VERSION 5.7 ;
  NOWIREEXTENSIONATPIN ON ;
  DIVIDERCHAR "/" ;
  BUSBITCHARS "[]" ;
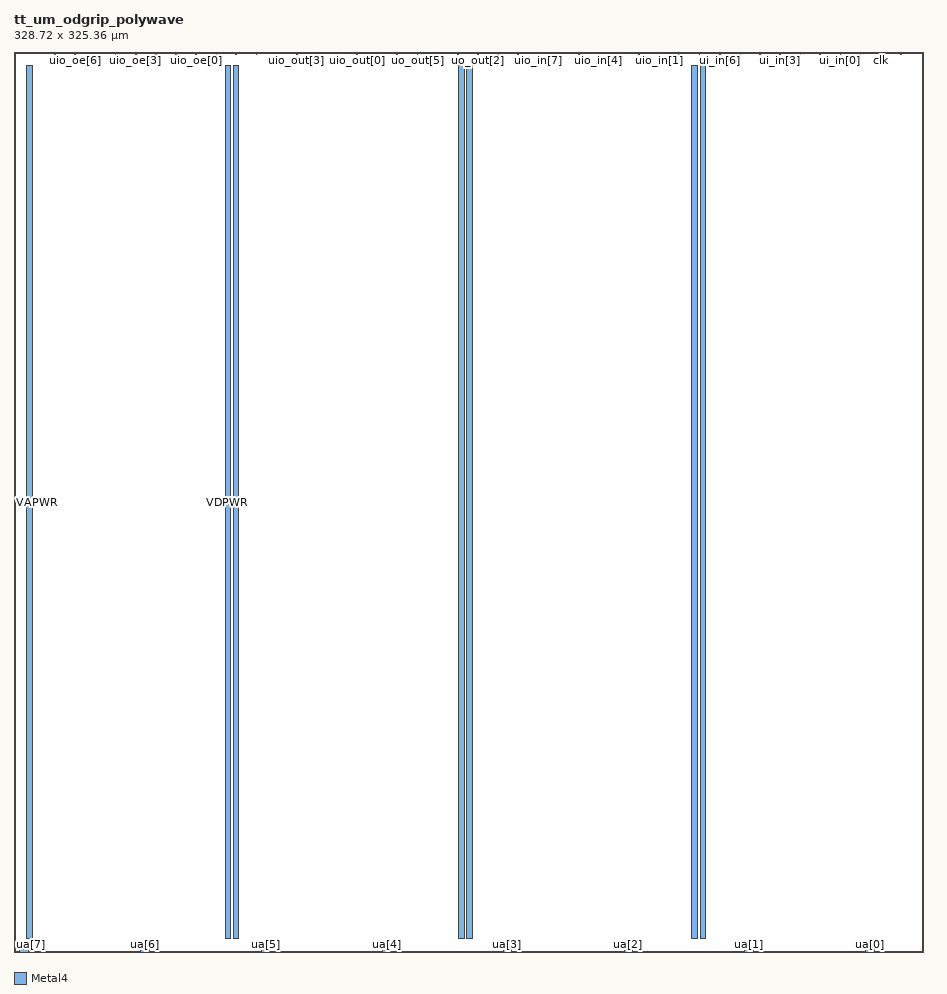
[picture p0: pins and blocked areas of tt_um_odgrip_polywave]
MACRO tt_um_odgrip_polywave
  CLASS BLOCK ;
  FOREIGN tt_um_odgrip_polywave ;
  ORIGIN 0.000 0.000 ;
  SIZE 328.720 BY 325.360 ;
  PIN clk
    DIRECTION INPUT ;
    USE SIGNAL ;
    PORT
      LAYER Metal4 ;
        RECT 313.170 324.360 313.470 325.360 ;
    END
  END clk
  PIN ena
    DIRECTION INPUT ;
    USE SIGNAL ;
    PORT
      LAYER Metal4 ;
        RECT 320.450 324.360 320.750 325.360 ;
    END
  END ena
  PIN rst_n
    DIRECTION INPUT ;
    USE SIGNAL ;
    PORT
      LAYER Metal4 ;
        RECT 305.890 324.360 306.190 325.360 ;
    END
  END rst_n
  PIN ua[0]
    DIRECTION INOUT ;
    USE SIGNAL ;
    PORT
      LAYER Metal4 ;
        RECT 307.900 0.000 310.900 1.000 ;
    END
  END ua[0]
  PIN ua[1]
    DIRECTION INOUT ;
    USE SIGNAL ;
    PORT
      LAYER Metal4 ;
        RECT 264.220 0.000 267.220 1.000 ;
    END
  END ua[1]
  PIN ua[2]
    DIRECTION INOUT ;
    USE SIGNAL ;
    PORT
      LAYER Metal4 ;
        RECT 220.540 0.000 223.540 1.000 ;
    END
  END ua[2]
  PIN ua[3]
    DIRECTION INOUT ;
    USE SIGNAL ;
    PORT
      LAYER Metal4 ;
        RECT 176.860 0.000 179.860 1.000 ;
    END
  END ua[3]
  PIN ua[4]
    DIRECTION INOUT ;
    USE SIGNAL ;
    PORT
      LAYER Metal4 ;
        RECT 133.180 0.000 136.180 1.000 ;
    END
  END ua[4]
  PIN ua[5]
    DIRECTION INOUT ;
    USE SIGNAL ;
    PORT
      LAYER Metal4 ;
        RECT 89.500 0.000 92.500 1.000 ;
    END
  END ua[5]
  PIN ua[6]
    DIRECTION INOUT ;
    USE SIGNAL ;
    PORT
      LAYER Metal4 ;
        RECT 45.820 0.000 48.820 1.000 ;
    END
  END ua[6]
  PIN ua[7]
    DIRECTION INOUT ;
    USE SIGNAL ;
    PORT
      LAYER Metal4 ;
        RECT 2.140 0.000 5.140 1.000 ;
    END
  END ua[7]
  PIN ui_in[0]
    DIRECTION INPUT ;
    USE SIGNAL ;
    PORT
      LAYER Metal4 ;
        RECT 298.610 324.360 298.910 325.360 ;
    END
  END ui_in[0]
  PIN ui_in[1]
    DIRECTION INPUT ;
    USE SIGNAL ;
    PORT
      LAYER Metal4 ;
        RECT 291.330 324.360 291.630 325.360 ;
    END
  END ui_in[1]
  PIN ui_in[2]
    DIRECTION INPUT ;
    USE SIGNAL ;
    PORT
      LAYER Metal4 ;
        RECT 284.050 324.360 284.350 325.360 ;
    END
  END ui_in[2]
  PIN ui_in[3]
    DIRECTION INPUT ;
    USE SIGNAL ;
    PORT
      LAYER Metal4 ;
        RECT 276.770 324.360 277.070 325.360 ;
    END
  END ui_in[3]
  PIN ui_in[4]
    DIRECTION INPUT ;
    USE SIGNAL ;
    PORT
      LAYER Metal4 ;
        RECT 269.490 324.360 269.790 325.360 ;
    END
  END ui_in[4]
  PIN ui_in[5]
    DIRECTION INPUT ;
    USE SIGNAL ;
    PORT
      LAYER Metal4 ;
        RECT 262.210 324.360 262.510 325.360 ;
    END
  END ui_in[5]
  PIN ui_in[6]
    DIRECTION INPUT ;
    USE SIGNAL ;
    PORT
      LAYER Metal4 ;
        RECT 254.930 324.360 255.230 325.360 ;
    END
  END ui_in[6]
  PIN ui_in[7]
    DIRECTION INPUT ;
    USE SIGNAL ;
    PORT
      LAYER Metal4 ;
        RECT 247.650 324.360 247.950 325.360 ;
    END
  END ui_in[7]
  PIN uio_in[0]
    DIRECTION INPUT ;
    USE SIGNAL ;
    PORT
      LAYER Metal4 ;
        RECT 240.370 324.360 240.670 325.360 ;
    END
  END uio_in[0]
  PIN uio_in[1]
    DIRECTION INPUT ;
    USE SIGNAL ;
    PORT
      LAYER Metal4 ;
        RECT 233.090 324.360 233.390 325.360 ;
    END
  END uio_in[1]
  PIN uio_in[2]
    DIRECTION INPUT ;
    USE SIGNAL ;
    PORT
      LAYER Metal4 ;
        RECT 225.810 324.360 226.110 325.360 ;
    END
  END uio_in[2]
  PIN uio_in[3]
    DIRECTION INPUT ;
    USE SIGNAL ;
    PORT
      LAYER Metal4 ;
        RECT 218.530 324.360 218.830 325.360 ;
    END
  END uio_in[3]
  PIN uio_in[4]
    DIRECTION INPUT ;
    USE SIGNAL ;
    PORT
      LAYER Metal4 ;
        RECT 211.250 324.360 211.550 325.360 ;
    END
  END uio_in[4]
  PIN uio_in[5]
    DIRECTION INPUT ;
    USE SIGNAL ;
    PORT
      LAYER Metal4 ;
        RECT 203.970 324.360 204.270 325.360 ;
    END
  END uio_in[5]
  PIN uio_in[6]
    DIRECTION INPUT ;
    USE SIGNAL ;
    PORT
      LAYER Metal4 ;
        RECT 196.690 324.360 196.990 325.360 ;
    END
  END uio_in[6]
  PIN uio_in[7]
    DIRECTION INPUT ;
    USE SIGNAL ;
    PORT
      LAYER Metal4 ;
        RECT 189.410 324.360 189.710 325.360 ;
    END
  END uio_in[7]
  PIN uio_oe[0]
    DIRECTION OUTPUT ;
    USE SIGNAL ;
    PORT
      LAYER Metal4 ;
        RECT 65.650 324.360 65.950 325.360 ;
    END
  END uio_oe[0]
  PIN uio_oe[1]
    DIRECTION OUTPUT ;
    USE SIGNAL ;
    PORT
      LAYER Metal4 ;
        RECT 58.370 324.360 58.670 325.360 ;
    END
  END uio_oe[1]
  PIN uio_oe[2]
    DIRECTION OUTPUT ;
    USE SIGNAL ;
    PORT
      LAYER Metal4 ;
        RECT 51.090 324.360 51.390 325.360 ;
    END
  END uio_oe[2]
  PIN uio_oe[3]
    DIRECTION OUTPUT ;
    USE SIGNAL ;
    PORT
      LAYER Metal4 ;
        RECT 43.810 324.360 44.110 325.360 ;
    END
  END uio_oe[3]
  PIN uio_oe[4]
    DIRECTION OUTPUT ;
    USE SIGNAL ;
    PORT
      LAYER Metal4 ;
        RECT 36.530 324.360 36.830 325.360 ;
    END
  END uio_oe[4]
  PIN uio_oe[5]
    DIRECTION OUTPUT ;
    USE SIGNAL ;
    PORT
      LAYER Metal4 ;
        RECT 29.250 324.360 29.550 325.360 ;
    END
  END uio_oe[5]
  PIN uio_oe[6]
    DIRECTION OUTPUT ;
    USE SIGNAL ;
    PORT
      LAYER Metal4 ;
        RECT 21.970 324.360 22.270 325.360 ;
    END
  END uio_oe[6]
  PIN uio_oe[7]
    DIRECTION OUTPUT ;
    USE SIGNAL ;
    PORT
      LAYER Metal4 ;
        RECT 14.690 324.360 14.990 325.360 ;
    END
  END uio_oe[7]
  PIN uio_out[0]
    DIRECTION OUTPUT ;
    USE SIGNAL ;
    PORT
      LAYER Metal4 ;
        RECT 123.890 324.360 124.190 325.360 ;
    END
  END uio_out[0]
  PIN uio_out[1]
    DIRECTION OUTPUT ;
    USE SIGNAL ;
    PORT
      LAYER Metal4 ;
        RECT 116.610 324.360 116.910 325.360 ;
    END
  END uio_out[1]
  PIN uio_out[2]
    DIRECTION OUTPUT ;
    USE SIGNAL ;
    PORT
      LAYER Metal4 ;
        RECT 109.330 324.360 109.630 325.360 ;
    END
  END uio_out[2]
  PIN uio_out[3]
    DIRECTION OUTPUT ;
    USE SIGNAL ;
    PORT
      LAYER Metal4 ;
        RECT 102.050 324.360 102.350 325.360 ;
    END
  END uio_out[3]
  PIN uio_out[4]
    DIRECTION OUTPUT ;
    USE SIGNAL ;
    PORT
      LAYER Metal4 ;
        RECT 94.770 324.360 95.070 325.360 ;
    END
  END uio_out[4]
  PIN uio_out[5]
    DIRECTION OUTPUT ;
    USE SIGNAL ;
    PORT
      LAYER Metal4 ;
        RECT 87.490 324.360 87.790 325.360 ;
    END
  END uio_out[5]
  PIN uio_out[6]
    DIRECTION OUTPUT ;
    USE SIGNAL ;
    PORT
      LAYER Metal4 ;
        RECT 80.210 324.360 80.510 325.360 ;
    END
  END uio_out[6]
  PIN uio_out[7]
    DIRECTION OUTPUT ;
    USE SIGNAL ;
    PORT
      LAYER Metal4 ;
        RECT 72.930 324.360 73.230 325.360 ;
    END
  END uio_out[7]
  PIN uo_out[0]
    DIRECTION OUTPUT ;
    USE SIGNAL ;
    PORT
      LAYER Metal4 ;
        RECT 182.130 324.360 182.430 325.360 ;
    END
  END uo_out[0]
  PIN uo_out[1]
    DIRECTION OUTPUT ;
    USE SIGNAL ;
    PORT
      LAYER Metal4 ;
        RECT 174.850 324.360 175.150 325.360 ;
    END
  END uo_out[1]
  PIN uo_out[2]
    DIRECTION OUTPUT ;
    USE SIGNAL ;
    PORT
      LAYER Metal4 ;
        RECT 167.570 324.360 167.870 325.360 ;
    END
  END uo_out[2]
  PIN uo_out[3]
    DIRECTION OUTPUT ;
    USE SIGNAL ;
    PORT
      LAYER Metal4 ;
        RECT 160.290 324.360 160.590 325.360 ;
    END
  END uo_out[3]
  PIN uo_out[4]
    DIRECTION OUTPUT ;
    USE SIGNAL ;
    PORT
      LAYER Metal4 ;
        RECT 153.010 324.360 153.310 325.360 ;
    END
  END uo_out[4]
  PIN uo_out[5]
    DIRECTION OUTPUT ;
    USE SIGNAL ;
    PORT
      LAYER Metal4 ;
        RECT 145.730 324.360 146.030 325.360 ;
    END
  END uo_out[5]
  PIN uo_out[6]
    DIRECTION OUTPUT ;
    USE SIGNAL ;
    PORT
      LAYER Metal4 ;
        RECT 138.450 324.360 138.750 325.360 ;
    END
  END uo_out[6]
  PIN uo_out[7]
    DIRECTION OUTPUT ;
    USE SIGNAL ;
    PORT
      LAYER Metal4 ;
        RECT 131.170 324.360 131.470 325.360 ;
    END
  END uo_out[7]
  PIN VDPWR
    DIRECTION INOUT ;
    USE POWER ;
    PORT
      LAYER Metal4 ;
        RECT 76.335 5.000 78.335 320.360 ;
    END
    PORT
      LAYER Metal4 ;
        RECT 160.725 5.000 162.725 320.360 ;
    END
    PORT
      LAYER Metal4 ;
        RECT 245.085 5.000 247.085 320.360 ;
    END
  END VDPWR
  PIN VGND
    DIRECTION INOUT ;
    USE GROUND ;
    PORT
      LAYER Metal4 ;
        RECT 79.335 5.000 81.335 320.360 ;
    END
    PORT
      LAYER Metal4 ;
        RECT 163.725 5.000 165.725 320.360 ;
    END
    PORT
      LAYER Metal4 ;
        RECT 248.085 5.000 250.085 320.360 ;
    END
  END VGND
  PIN VAPWR
    DIRECTION INOUT ;
    USE POWER ;
    PORT
      LAYER Metal4 ;
        RECT 4.580 5.000 6.580 320.360 ;
    END
  END VAPWR
END tt_um_odgrip_polywave
END LIBRARY
